One B-rep face of a CAD part: STEP entity #1461.
In plain terms, the planar face has unit normal (0, 1, 0).
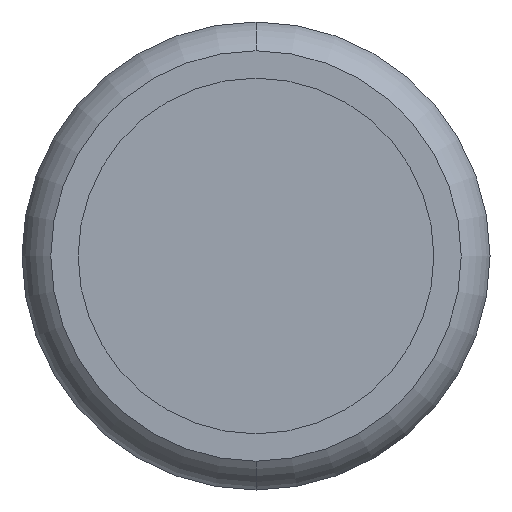
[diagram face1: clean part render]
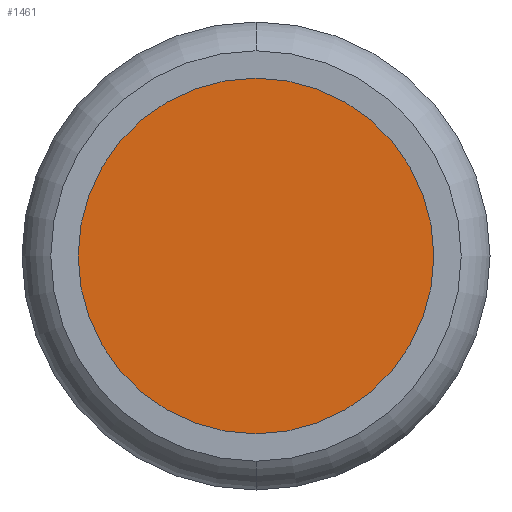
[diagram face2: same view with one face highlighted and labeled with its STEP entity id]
Its self-contained STEP definition (entity closure, numbers rounded to 3 decimals):
#1287 = EDGE_CURVE ( 'NONE', #3895, #3913, #6482, .T. ) ;
#1315 = EDGE_CURVE ( 'NONE', #3913, #3895, #6519, .T. ) ;
#1461 = ADVANCED_FACE ( 'NONE', ( #5470 ), #5454, .F. ) ;
#2128 = AXIS2_PLACEMENT_3D ( 'NONE', #5467, #5448, #5435 ) ;
#2685 = ORIENTED_EDGE ( 'NONE', *, *, #1315, .F. ) ;
#2721 = ORIENTED_EDGE ( 'NONE', *, *, #1287, .F. ) ;
#3895 = VERTEX_POINT ( 'NONE', #9595 ) ;
#3913 = VERTEX_POINT ( 'NONE', #9636 ) ;
#4396 = DIRECTION ( 'NONE',  ( 0., -1., 0. ) ) ;
#4412 = CARTESIAN_POINT ( 'NONE',  ( 0., 2.45, 0. ) ) ;
#4425 = DIRECTION ( 'NONE',  ( 0., 0., -1. ) ) ;
#4859 = DIRECTION ( 'NONE',  ( 0., 0., -1. ) ) ;
#4862 = CARTESIAN_POINT ( 'NONE',  ( 0., 2.45, 0. ) ) ;
#4870 = DIRECTION ( 'NONE',  ( 0., -1., 0. ) ) ;
#5435 = DIRECTION ( 'NONE',  ( 0., 0., -1. ) ) ;
#5448 = DIRECTION ( 'NONE',  ( 0., -1., 0. ) ) ;
#5454 = PLANE ( 'NONE',  #2128 ) ;
#5467 = CARTESIAN_POINT ( 'NONE',  ( -2.192, 2.45, 10. ) ) ;
#5470 = FACE_OUTER_BOUND ( 'NONE', #10538, .T. ) ;
#6482 = CIRCLE ( 'NONE', #6489, 1.9 ) ;
#6489 = AXIS2_PLACEMENT_3D ( 'NONE', #4412, #4396, #4425 ) ;
#6519 = CIRCLE ( 'NONE', #6520, 1.9 ) ;
#6520 = AXIS2_PLACEMENT_3D ( 'NONE', #4862, #4870, #4859 ) ;
#9595 = CARTESIAN_POINT ( 'NONE',  ( 0., 2.45, -1.9 ) ) ;
#9636 = CARTESIAN_POINT ( 'NONE',  ( 0., 2.45, 1.9 ) ) ;
#10538 = EDGE_LOOP ( 'NONE', ( #2685, #2721 ) ) ;
